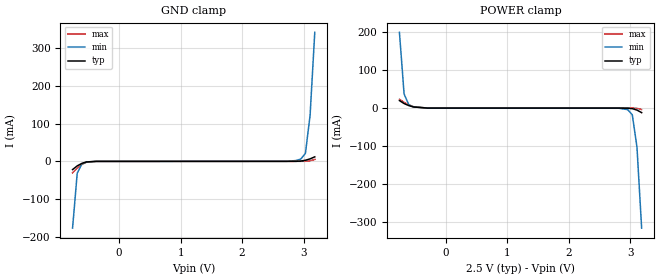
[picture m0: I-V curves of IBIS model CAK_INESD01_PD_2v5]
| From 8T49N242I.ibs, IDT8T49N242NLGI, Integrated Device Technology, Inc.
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| 3.25758e+00   -1.33581e-02   -4.69445e-01   -6.92786e-03
| 3.33333e+00   -3.05431e-02   -6.81022e-01   -1.35814e-02
| 3.40909e+00   -1.97473e-01   -8.92821e-01   -2.11713e-02
| 3.48485e+00   -4.80532e-01   -1.10478e+00   -2.82326e-02
| 3.56061e+00   -7.63803e-01   -1.31687e+00   -5.48408e-02
| 3.63636e+00   -1.04727e+00   -1.52909e+00   -3.40378e-01
| 3.71212e+00   -1.33091e+00   -1.74141e+00   -7.03030e-01
| 3.78788e+00   -1.61471e+00   -1.95383e+00   -1.06588e+00
| 3.86364e+00   -1.89867e+00   -2.16636e+00   -1.42892e+00
| 3.93939e+00   -2.18277e+00   -2.37898e+00   -1.79210e+00
| 4.01515e+00   -2.46699e+00   -2.59169e+00   -2.15542e+00
| 4.09091e+00   -2.75133e+00   -2.80449e+00   -2.51885e+00
| 4.16667e+00   -3.03577e+00   -3.01738e+00   -2.88238e+00
| 4.24242e+00   -3.32030e+00   -3.23034e+00   -3.24599e+00
| 4.31818e+00   -3.60492e+00   -3.44338e+00   -3.60966e+00
| 4.39394e+00   -3.88961e+00   -3.65649e+00   -3.97340e+00
| 4.46970e+00   -4.17436e+00   -3.86967e+00   -4.33720e+00
| 4.54545e+00   -4.45918e+00   -4.08291e+00   -4.70105e+00
| 4.62121e+00   -4.74404e+00   -4.29621e+00   -5.06495e+00
| 4.69697e+00   -5.02895e+00   -4.50957e+00   -5.42889e+00
| 4.77273e+00   -5.31390e+00   -4.72298e+00   -5.79286e+00
| 4.84848e+00   -5.59889e+00   -4.93644e+00   -6.15686e+00
| 4.92424e+00   -5.88390e+00   -5.14994e+00   -6.52088e+00
| 5.00000e+00   -6.16895e+00   -5.36349e+00   -6.88491e+00
[Model] CAK_INESD01_PD_2v5
Model_type   Input
Polarity   Non-Inverting
Vinl = 0.7V
Vinh = 1.7V
|   typ   min   max
C_comp   2pF   1.5pF   2.5pF
|   typ   min   max
[Voltage range]   2.5V   2.375V   2.625V
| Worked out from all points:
|   GND clamp passes 1 mA (typ) near -0.50 V on its own axis
|   POWER clamp passes 1 mA (typ) near -0.46 V on its own axis
[GND_clamp]
|Voltage   I (typ)   I (min)   I (max)
|Note, modeling breaks down at 250mA and above.  This is well beyond the functional   |
|operating range of the device.  Should this scenario occur, catastrophic failure and   |
|possible damage to the device and/or board is of higher concern than the I-V curve   |
|behavior.  The IBIS checker will flag currents in excess of 10A with warnings.  Lines   |
|with currents in excess of 0.35 A have been commented out.  The points still remain|
|available to the user if the user desires to use them.   |
|-2.50000e+00   -6.31277e+00   -5.12658e+00   -7.65734e+00
|-2.42424e+00   -6.02353e+00   -4.90997e+00   -7.28820e+00
|-2.34848e+00   -5.73432e+00   -4.69344e+00   -6.91907e+00
|-2.27273e+00   -5.44517e+00   -4.47699e+00   -6.54996e+00
|-2.19697e+00   -5.15608e+00   -4.26064e+00   -6.18087e+00
|-2.12121e+00   -4.86706e+00   -4.04438e+00   -5.81182e+00
|-2.04545e+00   -4.57811e+00   -3.82823e+00   -5.44281e+00
|-1.96970e+00   -4.28924e+00   -3.61218e+00   -5.07385e+00
|-1.89394e+00   -4.00047e+00   -3.39625e+00   -4.70495e+00
|-1.81818e+00   -3.71181e+00   -3.18045e+00   -4.33613e+00
|-1.74242e+00   -3.42327e+00   -2.96477e+00   -3.96740e+00
|-1.66667e+00   -3.13486e+00   -2.74923e+00   -3.59876e+00
|-1.59091e+00   -2.84661e+00   -2.53383e+00   -3.23023e+00
|-1.51515e+00   -2.55852e+00   -2.31859e+00   -2.86183e+00
|-1.43939e+00   -2.27062e+00   -2.10350e+00   -2.49356e+00
|-1.36364e+00   -1.98293e+00   -1.88857e+00   -2.12547e+00
|-1.28788e+00   -1.69546e+00   -1.67382e+00   -1.75758e+00
|-1.21212e+00   -1.40825e+00   -1.45924e+00   -1.38992e+00
|-1.13636e+00   -1.12130e+00   -1.24485e+00   -1.02253e+00
|-1.06061e+00   -8.34641e-01   -1.03066e+00   -6.55447e-01
|-9.84848e-01   -5.48303e-01   -8.16729e-01   -2.88713e-01
|-9.09091e-01   -2.62314e-01   -6.03115e-01   -6.18263e-02
|-8.33333e-01   -5.02723e-02   -3.89971e-01   -4.19557e-02
-757.6mV  -21.77mA   -176.8mA   -30.29mA
-681.8mV  -11.94mA   -31.43mA   -17.97mA
-606.1mV  -5.237mA   -6.649mA   -8.121mA
-530.3mV  -1.497mA   -1.616mA   -2.258mA
-378.8mV  -33.3uA    -60.55uA   -32.84uA
2.727V    54.7uA     148.5uA    62.76uA
2.879V    164.1uA    2.238mA    66.8uA
2.955V    851.6uA    6.163mA    82.77uA
3.03V     2.927mA    21.19mA    298.6uA
3.106V    6.608mA    122mA      1.706mA
3.182V    11.94mA    341.6mA    5.098mA
| 3.25758e+00   1.96970e-02   5.60151e-01   1.04728e-02
| 3.33333e+00   4.88005e-02   7.78612e-01   1.77353e-02
| 3.40909e+00   2.77157e-01   9.97242e-01   2.57387e-02
| 3.48485e+00   5.68838e-01   1.21608e+00   3.29072e-02
| 3.56061e+00   8.60782e-01   1.43512e+00   7.84004e-02
| 3.63636e+00   1.15301e+00   1.65439e+00   4.21035e-01
| 3.71212e+00   1.44553e+00   1.87386e+00   7.94492e-01
| 3.78788e+00   1.73833e+00   2.09355e+00   1.16831e+00
| 3.86364e+00   2.03142e+00   2.31345e+00   1.54249e+00
| 3.93939e+00   2.32478e+00   2.53356e+00   1.91701e+00
| 4.01515e+00   2.61841e+00   2.75389e+00   2.29187e+00
| 4.09091e+00   2.91230e+00   2.97442e+00   2.66707e+00
| 4.16667e+00   3.20646e+00   3.19517e+00   3.04258e+00
| 4.24242e+00   3.50087e+00   3.41613e+00   3.41840e+00
| 4.31818e+00   3.79553e+00   3.63729e+00   3.79452e+00
| 4.39394e+00   4.09044e+00   3.85868e+00   4.17093e+00
| 4.46970e+00   4.38559e+00   4.08027e+00   4.54762e+00
| 4.54545e+00   4.68099e+00   4.30208e+00   4.92458e+00
| 4.62121e+00   4.97663e+00   4.52411e+00   5.30181e+00
| 4.69697e+00   5.27250e+00   4.74637e+00   5.67930e+00
| 4.77273e+00   5.56862e+00   4.96885e+00   6.05705e+00
| 4.84848e+00   5.86497e+00   5.19156e+00   6.43505e+00
| 4.92424e+00   6.16156e+00   5.41450e+00   6.81329e+00
| 5.00000e+00   6.45839e+00   5.63769e+00   7.19178e+00
[Power_clamp]
|Voltage   I (typ)   I (min)   I (max)
|Note, modeling breaks down at 250mA and above.  This is well beyond the functional   |
|operating range of the device.  Should this scenario occur, catastrophic failure and   |
|possible damage to the device and/or board is of higher concern than the I-V curve   |
|behavior.  The IBIS checker will flag currents in excess of 10A with warnings.  Lines   |
|with currents in excess of 0.35 A have been commented out.  The points still remain|
|available to the user if the user desires to use them.   |
|-2.50000e+00   6.45839e+00   5.26956e+00   7.81682e+00
|-2.42424e+00   6.16156e+00   5.04677e+00   7.43793e+00
|-2.34848e+00   5.86497e+00   4.82421e+00   7.05928e+00
|-2.27273e+00   5.56862e+00   4.60188e+00   6.68088e+00
|-2.19697e+00   5.27250e+00   4.37977e+00   6.30272e+00
|-2.12121e+00   4.97663e+00   4.15788e+00   5.92481e+00
|-2.04545e+00   4.68099e+00   3.93621e+00   5.54715e+00
|-1.96970e+00   4.38559e+00   3.71475e+00   5.16975e+00
|-1.89394e+00   4.09044e+00   3.49351e+00   4.79261e+00
|-1.81818e+00   3.79553e+00   3.27248e+00   4.41574e+00
|-1.74242e+00   3.50087e+00   3.05166e+00   4.03915e+00
|-1.66667e+00   3.20646e+00   2.83105e+00   3.66284e+00
|-1.59091e+00   2.91230e+00   2.61065e+00   3.28683e+00
|-1.51515e+00   2.61841e+00   2.39047e+00   2.91111e+00
|-1.43939e+00   2.32478e+00   2.17049e+00   2.53571e+00
|-1.36364e+00   2.03142e+00   1.95073e+00   2.16063e+00
|-1.28788e+00   1.73833e+00   1.73118e+00   1.78589e+00
|-1.21212e+00   1.44553e+00   1.51184e+00   1.41148e+00
|-1.13636e+00   1.15301e+00   1.29272e+00   1.03743e+00
|-1.06061e+00   8.60782e-01   1.07381e+00   6.63741e-01
|-9.84848e-01   5.68838e-01   8.55110e-01   2.90410e-01
|-9.09091e-01   2.77157e-01   6.36598e-01   4.68691e-02
|-8.33333e-01   4.88005e-02   4.18165e-01   3.01369e-02
-757.6mV  19.7mA     199mA      23.06mA
-681.8mV  11.94mA    37.05mA    15mA
-606.1mV  6.608mA    9.022mA    8.369mA
-530.3mV  2.927mA    3.211mA    3.683mA
-303mV    64.26uA    72.07uA    72.59uA
2.803V    -7.9uA     -185.8uA   -4.1uA
2.955V    -253.9uA   -4.064mA   -10.75uA
3.03V     -1.497mA   -17.62mA   -73.27uA
3.106V    -5.237mA   -102.4mA   -686.5uA
3.182V    -11.94mA   -315.5mA   -3.8mA
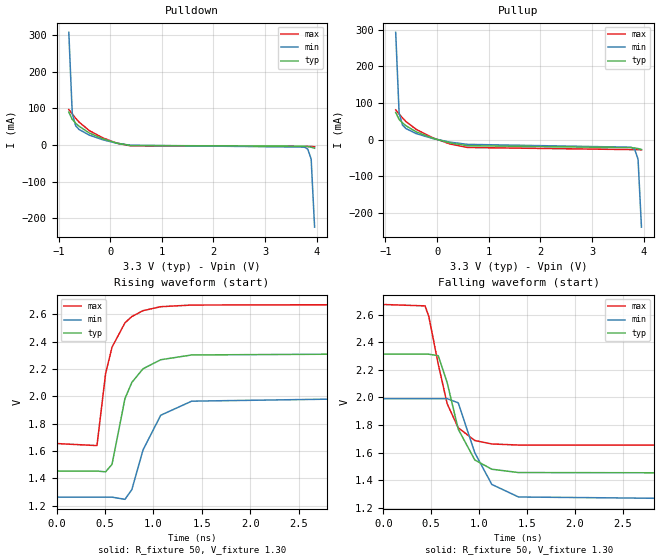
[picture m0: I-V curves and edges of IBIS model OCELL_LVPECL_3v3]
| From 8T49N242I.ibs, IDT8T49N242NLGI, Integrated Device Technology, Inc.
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[Model] OCELL_LVPECL_3v3
Model_type   Output_ECL
Polarity   Non-Inverting
|   typ   min   max
C_comp   2pF   1.5pF   2.5pF
Vmeas= 1.981V
Rref = 50
Cref = 0
Vref = 1.3V
|   typ   min   max
[Voltage range]   3.3V   3.135V   3.465V
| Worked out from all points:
|   rising waveform, R_fixture 50, V_fixture 1.30: 20-80 % time 209ps typ, 237ps min, 177ps max; typ from 1.45 V to 2.31 V
|   falling waveform, R_fixture 50, V_fixture 1.30: 20-80 % time 216ps typ, 236ps min, 208ps max; typ from 2.31 V to 1.45 V
[Pulldown]
|Voltage   I (typ)   I (min)   I (max)
|Note, modeling breaks down at 250mA and above.  This is well beyond the functional   |
|operating range of the device.  Should this scenario occur, catastrophic failure and   |
|possible damage to the device and/or board is of higher concern than the I-V curve   |
|behavior.  The IBIS checker will flag currents in excess of 10A with warnings.  Lines   |
|with currents in excess of 0.35 A have been commented out.  The points still remain|
|available to the user if the user desires to use them.   |
|-2.84000e+00   4.48642e+01   3.88809e+01   5.49794e+01
|-2.38000e+00   3.43286e+01   3.01080e+01   4.15134e+01
|-1.92000e+00   2.38016e+01   2.13440e+01   2.80562e+01
|-1.46000e+00   1.32831e+01   1.25878e+01   1.46080e+01
|-1.00000e+00   2.77295e+00   3.83912e+00   1.17156e+00
|-9.99000e-01   2.75011e+00   3.82010e+00   1.14339e+00
|-9.32920e-01   1.24105e+00   2.56387e+00   1.69185e-01
|-8.66839e-01   2.23568e-01   1.30764e+00   1.07771e-01
-800.8mV  89.63mA    307.4mA    96.46mA
-734.7mV  69.89mA    86.68mA    84.78mA
-668.6mV  59.44mA    52.31mA    72.85mA
-602.5mV  50.96mA    42.16mA    62.33mA
-404.3mV  32.46mA    26.75mA    39.06mA
-140mV    16.53mA    13.94mA    19.11mA
124.4mV   5.033mA    4.656mA    4.981mA
388.7mV   -1.547mA   -975.2uA   -2.433mA
3.759V    -3.557mA   -5.879mA   -4.136mA
3.825V    -4.347mA   -11.53mA   -4.168mA
3.891V    -6.158mA   -38.84mA   -4.315mA
3.957V    -9.133mA   -224.5mA   -4.982mA
| 4.02311e+00   -1.33518e-02   -8.12183e-01   -6.92223e-03
| 4.08920e+00   -2.10699e-02   -1.42227e+00   -1.05319e-02
| 4.15528e+00   -6.28947e-02   -2.03255e+00   -1.56059e-02
| 4.22136e+00   -4.54421e-01   -2.64299e+00   -2.16909e-02
| 4.28744e+00   -1.18742e+00   -3.25354e+00   -2.78770e-02
| 4.35352e+00   -1.92063e+00   -3.86420e+00   -3.65827e-02
| 4.41960e+00   -2.65404e+00   -4.47496e+00   -1.11095e-01
| 4.48568e+00   -3.38765e+00   -5.08580e+00   -8.43366e-01
| 4.55176e+00   -4.12145e+00   -5.69673e+00   -1.78115e+00
| 4.61784e+00   -4.85540e+00   -6.30773e+00   -2.71906e+00
| 4.68392e+00   -5.58948e+00   -6.91882e+00   -3.65709e+00
| 4.75000e+00   -6.32368e+00   -7.52997e+00   -4.59521e+00
| 4.75100e+00   -6.33479e+00   -7.53922e+00   -4.60941e+00
| 5.12080e+00   -1.04451e+01   -1.09605e+01   -9.86150e+00
| 5.49060e+00   -1.45574e+01   -1.43834e+01   -1.51175e+01
| 5.86040e+00   -1.86708e+01   -1.78076e+01   -2.03750e+01
| 6.23020e+00   -2.27853e+01   -2.12327e+01   -2.56335e+01
| 6.60000e+00   -2.69005e+01   -2.46588e+01   -3.08927e+01
[Pullup]
|Voltage   I (typ)   I (min)   I (max)
|Note, modeling breaks down at 250mA and above.  This is well beyond the functional   |
|operating range of the device.  Should this scenario occur, catastrophic failure and   |
|possible damage to the device and/or board is of higher concern than the I-V curve   |
|behavior.  The IBIS checker will flag currents in excess of 10A with warnings.  Lines   |
|with currents in excess of 0.35 A have been commented out.  The points still remain|
|available to the user if the user desires to use them.   |
|-2.84000e+00   4.48913e+01   3.89061e+01   5.50071e+01
|-2.38000e+00   3.43461e+01   3.01266e+01   4.15290e+01
|-1.92000e+00   2.38063e+01   2.13516e+01   2.80582e+01
|-1.46000e+00   1.32762e+01   1.25834e+01   1.46037e+01
|-1.00000e+00   2.75940e+00   3.82623e+00   1.15897e+00
|-9.99000e-01   2.73655e+00   3.80721e+00   1.13078e+00
|-9.32920e-01   1.22670e+00   2.55036e+00   1.55505e-01
|-8.66839e-01   2.08561e-01   1.29365e+00   9.31426e-02
-800.8mV  74.27mA    293.2mA    81.23mA
-734.7mV  55.04mA    73.06mA    69.96mA
-668.6mV  45.51mA    39.53mA    58.99mA
-602.5mV  37.86mA    30.13mA    49.37mA
-404.3mV  21.16mA    16.4mA     27.88mA
-73.87mV  3.267mA    2.499mA    4.372mA
256.5mV   -9.246mA   -7.115mA   -12.28mA
586.9mV   -16.69mA   -13.1mA    -21.59mA
3.759V    -22.12mA   -20.94mA   -27.4mA
3.825V    -22.83mA   -26.45mA   -27.43mA
3.891V    -24.49mA   -53.7mA    -27.55mA
3.957V    -27.14mA   -239.4mA   -28.1mA
| 4.02311e+00   -3.09440e-02   -8.27120e-01   -2.98830e-02
| 4.08920e+00   -3.82573e-02   -1.43726e+00   -3.31930e-02
| 4.15528e+00   -7.98137e-02   -2.04759e+00   -3.77654e-02
| 4.22136e+00   -4.71273e-01   -2.65806e+00   -4.32916e-02
| 4.28744e+00   -1.20438e+00   -3.26865e+00   -4.89558e-02
| 4.35352e+00   -1.93780e+00   -3.87934e+00   -5.71946e-02
| 4.41960e+00   -2.67145e+00   -4.49011e+00   -1.31258e-01
| 4.48568e+00   -3.40528e+00   -5.10098e+00   -8.63090e-01
| 4.55176e+00   -4.13926e+00   -5.71192e+00   -1.80052e+00
| 4.61784e+00   -4.87336e+00   -6.32294e+00   -2.73834e+00
| 4.68392e+00   -5.60755e+00   -6.93403e+00   -3.67651e+00
| 4.75000e+00   -6.34184e+00   -7.54520e+00   -4.61495e+00
| 4.75100e+00   -6.35295e+00   -7.55445e+00   -4.62916e+00
| 5.12080e+00   -1.04636e+01   -1.09758e+01   -9.88370e+00
| 5.49060e+00   -1.45760e+01   -1.43989e+01   -1.51404e+01
| 5.86040e+00   -1.86897e+01   -1.78233e+01   -2.03983e+01
| 6.23020e+00   -2.28047e+01   -2.12489e+01   -2.56574e+01
| 6.60000e+00   -2.69208e+01   -2.46757e+01   -3.09176e+01
[Ramp]
|   typ   min   max
dV/dt_r   0.526/0.208n   0.446/0.238n   0.62/0.176n
dV/dt_f   0.516/0.215n   0.437/0.236n   0.611/0.207n
R_load =   50.0000
[Rising Waveform]
R_fixture = 50
V_fixture = 1.30   | VCC_typ - 2V
V_fixture_max = 1.465   | VCC_max - 2V
V_fixture_min = 1.135   | VCC_min - 2V
C_fixture = 0.0p
| Time   typ   min   max
0s        1.453V     1.262V     1.654V
417.8ps   1.453V     1.262V     1.639V
506.7ps   1.447V     1.262V     2.165V
573.3ps   1.502V     1.262V     2.359V
706.7ps   1.983V     1.246V     2.537V
777.8ps   2.101V     1.317V     2.583V
893.3ps   2.201V     1.607V     2.626V
1.076ns   2.267V     1.861V     2.655V
1.396ns   2.302V     1.964V     2.667V
4ns       2.312V     1.991V     2.671V
[Falling Waveform]
R_fixture = 50
V_fixture = 1.30   | VCC_typ - 2V
V_fixture_max = 1.465   | VCC_max - 2V
V_fixture_min = 1.135   | VCC_min - 2V
C_fixture = 0.0p
| Time   typ   min   max
0s        2.314V     1.991V     2.673V
435.6ps   2.314V     1.991V     2.663V
475.6ps   2.313V     1.991V     2.583V
573.3ps   2.302V     1.991V     2.241V
666.7ps   2.107V     1.991V     1.954V
782.2ps   1.77V      1.961V     1.78V
955.6ps   1.547V     1.599V     1.688V
1.133ns   1.48V      1.37V      1.663V
1.413ns   1.456V     1.279V     1.655V
4ns       1.453V     1.262V     1.654V
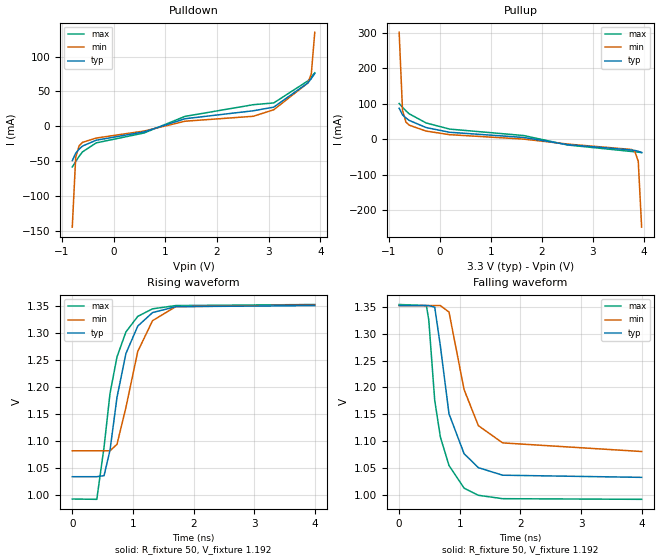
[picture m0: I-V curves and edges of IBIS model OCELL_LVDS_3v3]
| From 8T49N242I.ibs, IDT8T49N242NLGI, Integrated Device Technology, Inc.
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[Model] OCELL_LVDS_3v3
Model_type   Output
Polarity   Non-Inverting
|   typ   min   max
C_comp   2pF   1.5pF   2.5pF
Vmeas = 1.196V
Rref = 50
Cref = 0
Vref = 1.196V
|   typ   min   max
[Voltage range]   3.3V   3.135V   3.465V
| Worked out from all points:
|   slope of the pulldown table from 0 to 0.495 V, typ, clamps not added: 80.3 ohm
|   slope of the pullup table from 0 to 0.495 V, typ, clamps not added: 59.6 ohm
|   rising waveform, R_fixture 50, V_fixture 1.192: 20-80 % time 323ps typ, 342ps min, 301ps max; typ from 1.03 V to 1.35 V
|   falling waveform, R_fixture 50, V_fixture 1.192: 20-80 % time 300ps typ, 367ps min, 274ps max; typ from 1.35 V to 1.03 V
[Pulldown]
|Voltage   I (typ)   I (min)   I (max)
|Note, modeling breaks down at 250mA and above.  This is well beyond the functional   |
|operating range of the device.  Should this scenario occur, catastrophic failure and   |
|possible damage to the device and/or board is of higher concern than the I-V curve   |
|behavior.  The IBIS checker will flag currents in excess of 10A with warnings.  Lines   |
|with currents in excess of 0.35 A have been commented out.  The points still remain|
|available to the user if the user desires to use them.   |
|-2.84000e+00   -2.18312e+01   -1.89112e+01   -2.67563e+01
|-2.38000e+00   -1.67158e+01   -1.46508e+01   -2.02208e+01
|-1.92000e+00   -1.15995e+01   -1.03922e+01   -1.36805e+01
|-1.46000e+00   -6.47957e+00   -6.13294e+00   -7.13256e+00
|-1.00000e+00   -1.35728e+00   -1.87225e+00   -5.87189e-01
|-9.99000e-01   -1.34615e+00   -1.86299e+00   -5.72979e-01
|-9.32920e-01   -6.11184e-01   -1.25100e+00   -9.89137e-02
|-8.66839e-01   -1.12398e-01   -6.39175e-01   -6.67640e-02
-800.8mV  -49.21mA   -144.5mA   -58.28mA
-734.7mV  -38.48mA   -44.53mA   -50.46mA
-668.6mV  -32.71mA   -27.76mA   -42.99mA
-602.5mV  -28.21mA   -22.9mA    -36.53mA
-338.2mV  -19.9mA    -16.78mA   -23.69mA
586.9mV   -7.953mA   -6.723mA   -9.531mA
1.38V     10.94mA    7.367mA    14.29mA
2.702V    22.33mA    14.44mA    31.06mA
3.098V    27.57mA    23.83mA    33.6mA
3.759V    62.35mA    62.26mA    65.21mA
3.825V    68.54mA    75.55mA    70.7mA
3.891V    75.8mA     134.8mA    76.8mA
| 3.95703e+00   8.42203e-02   5.53371e-01   8.40055e-02
| 4.02311e+00   9.42015e-02   1.72709e+00   9.25435e-02
| 4.08920e+00   1.10184e-01   2.98252e+00   1.02465e-01
| 4.15528e+00   1.98873e-01   4.23802e+00   1.13812e-01
| 4.22136e+00   1.01164e+00   5.49363e+00   1.26115e-01
| 4.28744e+00   2.51012e+00   6.74938e+00   1.36748e-01
| 4.35352e+00   4.01871e+00   8.00527e+00   1.51173e-01
| 4.41960e+00   5.52743e+00   9.26131e+00   3.10394e-01
| 4.48568e+00   7.03630e+00   1.05175e+01   1.80868e+00
| 4.55176e+00   8.54533e+00   1.17739e+01   3.73807e+00
| 4.61784e+00   1.00545e+01   1.30305e+01   5.66764e+00
| 4.68392e+00   1.15639e+01   1.42873e+01   7.59739e+00
| 4.75000e+00   1.30734e+01   1.55443e+01   9.52731e+00
| 4.75100e+00   1.30963e+01   1.55633e+01   9.55651e+00
| 5.12080e+00   2.15474e+01   2.26012e+01   2.03599e+01
| 5.49060e+00   3.00052e+01   2.96454e+01   3.11693e+01
| 5.86040e+00   3.84699e+01   3.66966e+01   4.19859e+01
| 6.23020e+00   4.69413e+01   4.37552e+01   5.28096e+01
| 6.60000e+00   5.54200e+01   5.08210e+01   6.36401e+01
[Pullup]
|Voltage   I (typ)   I (min)   I (max)
|Note, modeling breaks down at 250mA and above.  This is well beyond the functional   |
|operating range of the device.  Should this scenario occur, catastrophic failure and   |
|possible damage to the device and/or board is of higher concern than the I-V curve   |
|behavior.  The IBIS checker will flag currents in excess of 10A with warnings.  Lines   |
|with currents in excess of 0.35 A have been commented out.  The points still remain|
|available to the user if the user desires to use them.   |
|-2.84000e+00   4.48945e+01   3.89013e+01   5.50181e+01
|-2.38000e+00   3.43501e+01   3.01230e+01   4.15408e+01
|-1.92000e+00   2.38122e+01   2.13501e+01   2.80719e+01
|-1.46000e+00   1.32853e+01   1.25851e+01   1.46193e+01
|-1.00000e+00   2.77065e+00   3.83231e+00   1.17641e+00
|-9.99000e-01   2.74780e+00   3.81330e+00   1.14823e+00
|-9.32920e-01   1.23836e+00   2.55689e+00   1.73378e-01
|-8.66839e-01   2.20683e-01   1.30064e+00   1.11531e-01
-800.8mV  86.99mA    300.7mA    100.3mA
-734.7mV  68.51mA    81.19mA    89.95mA
-668.6mV  59.69mA    48.2mA     79.91mA
-602.5mV  52.74mA    39.3mA     71.25mA
-272.1mV  32.65mA    22.7mA     45.61mA
190.4mV   19.37mA    12.6mA     28.31mA
1.644V    4.765mA    146.4uA    10.17mA
2.503V    -15.36mA   -13.82mA   -16.44mA
3.759V    -30.52mA   -29.05mA   -34.71mA
3.825V    -31.86mA   -34.94mA   -35.64mA
3.891V    -34.12mA   -62.29mA   -36.63mA
3.957V    -37.52mA   -247.7mA   -37.98mA
| 4.02311e+00   -4.20682e-02   -8.34837e-01   -4.04588e-02
| 4.08920e+00   -4.98977e-02   -1.44435e+00   -4.45673e-02
| 4.15528e+00   -9.15363e-02   -2.05400e+00   -5.00520e-02
| 4.22136e+00   -4.82768e-01   -2.66375e+00   -5.63548e-02
| 4.28744e+00   -1.21540e+00   -3.27360e+00   -6.23914e-02
| 4.35352e+00   -1.94816e+00   -3.88353e+00   -7.07124e-02
| 4.41960e+00   -2.68104e+00   -4.49355e+00   -1.44778e-01
| 4.48568e+00   -3.41402e+00   -5.10364e+00   -8.76569e-01
| 4.55176e+00   -4.14711e+00   -5.71380e+00   -1.81385e+00
| 4.61784e+00   -4.88028e+00   -6.32403e+00   -2.75125e+00
| 4.68392e+00   -5.61355e+00   -6.93432e+00   -3.68875e+00
| 4.75000e+00   -6.34689e+00   -7.54468e+00   -4.62636e+00
| 4.75100e+00   -6.35799e+00   -7.55392e+00   -4.64055e+00
| 5.12080e+00   -1.04632e+01   -1.09708e+01   -9.88889e+00
| 5.49060e+00   -1.45702e+01   -1.43911e+01   -1.51388e+01
| 5.86040e+00   -1.86801e+01   -1.78140e+01   -2.03900e+01
| 6.23020e+00   -2.27925e+01   -2.12380e+01   -2.56432e+01
| 6.60000e+00   -2.69059e+01   -2.46629e+01   -3.08994e+01
[Ramp]
|   typ   min   max
dV/dt_r   0.19/0.323n   0.163/0.35n   0.216/0.3n
dV/dt_f   0.192/0.299n   0.163/0.366n   0.217/0.273n
R_load =   50.0000
[Rising Waveform]
R_fixture = 50
V_fixture   =1.192  |Vcc_typ
V_fixture_min=1.216  |Vcc_min
V_fixture_max=1.173  |Vcc_max
C_fixture = 0.0p
| Time   typ   min   max
0s        1.034V     1.082V     992.7mV
404.4ps   1.034V     1.082V     992.1mV
524.4ps   1.036V     1.082V     1.089V
622.2ps   1.083V     1.082V     1.188V
737.8ps   1.181V     1.094V     1.256V
884.4ps   1.262V     1.162V     1.302V
1.08ns    1.313V     1.266V     1.331V
1.324ns   1.338V     1.323V     1.345V
1.707ns   1.349V     1.349V     1.351V
4ns       1.351V     1.352V     1.353V
[Falling Waveform]
R_fixture = 50
V_fixture   =1.192  |Vcc_typ
V_fixture_min=1.216  |Vcc_min
V_fixture_max=1.173  |Vcc_max
C_fixture = 0.0p
| Time   typ   min   max
0s        1.352V     1.352V     1.354V
448.9ps   1.352V     1.352V     1.352V
488.9ps   1.352V     1.352V     1.325V
586.7ps   1.349V     1.352V     1.176V
680ps     1.277V     1.352V     1.108V
822.2ps   1.151V     1.34V      1.055V
1.071ns   1.077V     1.196V     1.013V
1.307ns   1.051V     1.129V     999.7mV
1.707ns   1.037V     1.097V     993.4mV
4ns       1.033V     1.081V     992.2mV
